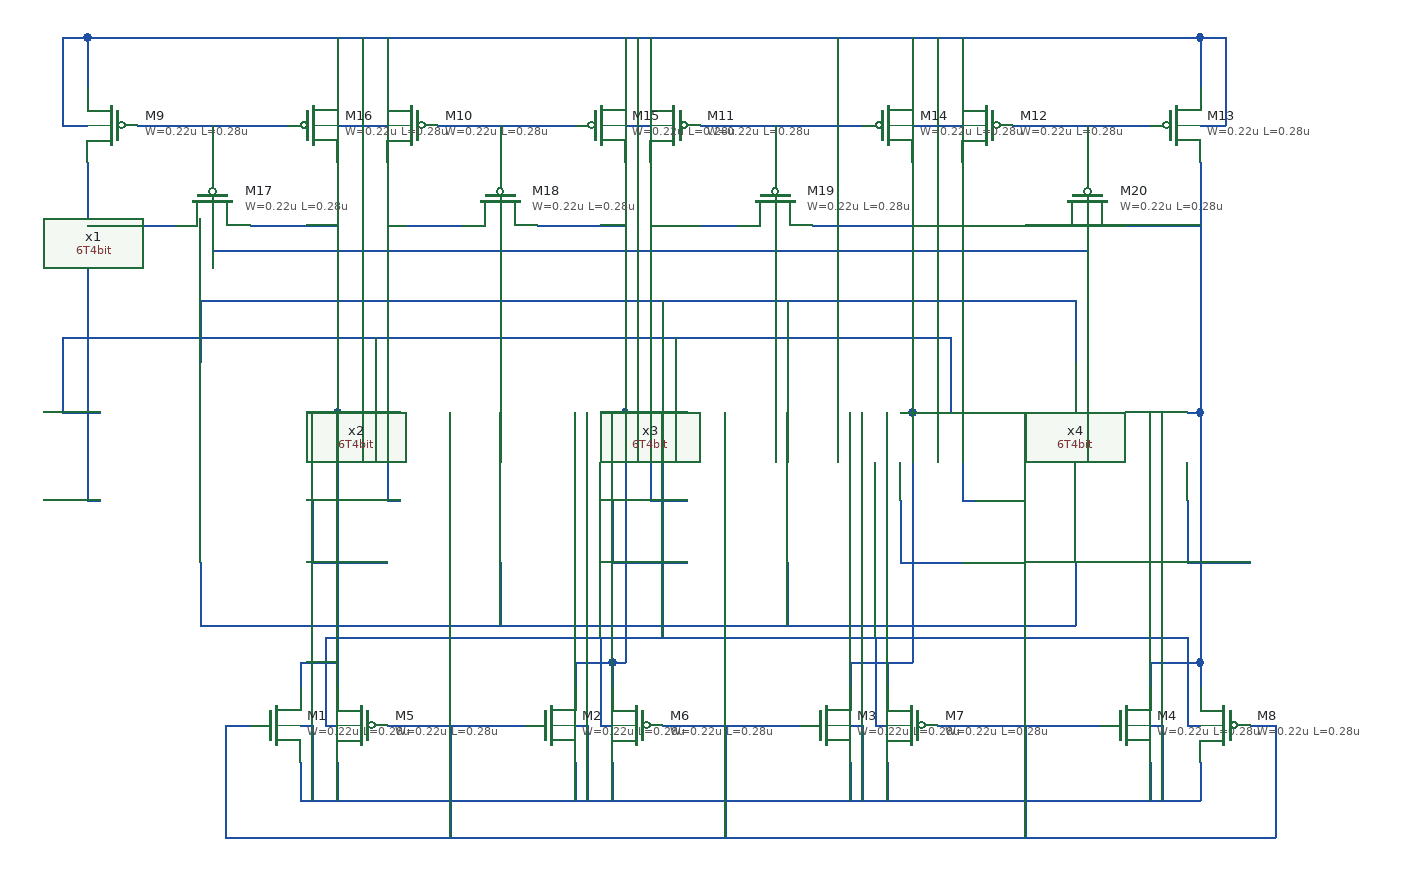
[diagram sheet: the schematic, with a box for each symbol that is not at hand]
v {xschem version=3.4.8RC file_version=1.3}
G {}
K {}
V {}
S {}
F {}
E {}
N 550 -130 550 -80 {lab=#net1}
N -150 -130 550 -130 {lab=#net1}
N -150 -130 -150 -80 {lab=#net1}
N 90 -130 90 -80 {lab=#net1}
N 320 -130 320 -80 {lab=#net1}
N -150 80 -150 130 {lab=#net2}
N -150 130 550 130 {lab=#net2}
N 550 80 550 130 {lab=#net2}
N 320 80 320 130 {lab=#net2}
N 90 80 90 130 {lab=#net2}
N 650 160 650 180 {lab=#net3}
N 610 160 650 160 {lab=#net3}
N 610 160 610 180 {lab=#net3}
N -70 240 -70 270 {lab=#net4}
N -70 270 650 270 {lab=#net4}
N 650 240 650 270 {lab=#net4}
N 610 240 610 270 {lab=#net4}
N 400 240 400 270 {lab=#net4}
N 370 240 370 270 {lab=#net4}
N 180 240 180 270 {lab=#net4}
N 150 240 150 270 {lab=#net4}
N -40 240 -40 270 {lab=#net4}
N -70 160 -70 180 {lab=#net5}
N -70 160 -40 160 {lab=#net5}
N 150 160 150 180 {lab=#net6}
N 150 160 180 160 {lab=#net6}
N 180 160 180 180 {lab=#net6}
N 370 160 370 180 {lab=#net1}
N 400 160 400 180 {lab=#net1}
N 410 -40 420 -40 {lab=#net1}
N 420 -40 420 160 {lab=#net1}
N 390 160 420 160 {lab=#net1}
N 370 160 390 160 {lab=#net1}
N 640 -40 650 -40 {lab=#net3}
N 650 -40 650 160 {lab=#net3}
N 180 -40 190 -40 {lab=#net6}
N 190 -40 190 160 {lab=#net6}
N 180 160 190 160 {lab=#net6}
N -60 -40 -40 -40 {lab=#net5}
N -40 -40 -40 170 {lab=#net5}
N -40 170 -40 180 {lab=#net5}
N -70 210 -60 210 {lab=#net4}
N -60 210 -60 270 {lab=#net4}
N 150 210 160 210 {lab=#net4}
N 160 210 160 270 {lab=#net4}
N 370 210 380 210 {lab=#net4}
N 380 210 380 270 {lab=#net4}
N 610 210 620 210 {lab=#net4}
N 620 210 620 270 {lab=#net4}
N -0 210 110 210 {lab=#net7}
N 220 210 330 210 {lab=#net7}
N 440 210 570 210 {lab=#net7}
N -130 210 -110 210 {lab=#net7}
N -130 210 -130 300 {lab=#net7}
N -130 300 710 300 {lab=#net7}
N 710 210 710 300 {lab=#net7}
N 690 210 710 210 {lab=#net7}
N 510 210 510 300 {lab=#net7}
N 270 210 270 300 {lab=#net7}
N 50 220 50 300 {lab=#net7}
N 50 210 50 220 {lab=#net7}
N -50 210 -40 210 {lab=#net1}
N -50 140 -50 210 {lab=#net1}
N -50 140 640 140 {lab=#net1}
N 640 140 640 210 {lab=#net1}
N 640 210 650 210 {lab=#net1}
N 390 210 400 210 {lab=#net1}
N 390 140 390 210 {lab=#net1}
N 170 210 180 210 {lab=#net1}
N 170 140 170 210 {lab=#net1}
N 220 -130 220 140 {lab=#net1}
N 450 -40 470 -40 {lab=#net8}
N 450 -100 450 -40 {lab=#net8}
N -260 -100 450 -100 {lab=#net8}
N -260 -100 -260 -40 {lab=#net8}
N -260 -40 -230 -40 {lab=#net8}
N -10 -40 10 -40 {lab=#net8}
N -10 -100 -10 -40 {lab=#net8}
N 230 -40 240 -40 {lab=#net8}
N 230 -100 230 -40 {lab=#net8}
N -240 30 -230 30 {lab=#net9}
N -240 -180 -240 30 {lab=#net9}
N -40 -240 -40 -40 {lab=#net5}
N -240 -240 -240 -180 {lab=#net9}
N 0 30 10 30 {lab=#net10}
N -0 -240 -0 30 {lab=#net10}
N 190 -240 190 -40 {lab=#net6}
N 210 30 240 30 {lab=#net11}
N 210 -240 210 30 {lab=#net11}
N 420 -240 420 -40 {lab=#net1}
N 460 30 470 30 {lab=#net12}
N 460 -240 460 30 {lab=#net12}
N 650 -240 650 -40 {lab=#net3}
N -200 -270 -80 -270 {lab=#net13}
N 40 -270 150 -270 {lab=#net14}
N 250 -270 380 -270 {lab=#net15}
N 500 -270 610 -270 {lab=#net16}
N -240 -340 -240 -300 {lab=#net17}
N -240 -340 650 -340 {lab=#net17}
N 650 -340 650 -300 {lab=#net17}
N 460 -340 460 -300 {lab=#net17}
N 420 -340 420 -300 {lab=#net17}
N 210 -340 210 -300 {lab=#net17}
N 190 -340 190 -300 {lab=#net17}
N 0 -340 0 -300 {lab=#net17}
N -40 -340 -40 -300 {lab=#net17}
N -260 -270 -240 -270 {lab=#net17}
N -260 -340 -260 -270 {lab=#net17}
N -260 -340 -240 -340 {lab=#net17}
N -40 -270 -0 -270 {lab=#net17}
N -20 -340 -20 -270 {lab=#net17}
N 190 -270 210 -270 {lab=#net17}
N 200 -340 200 -270 {lab=#net17}
N 420 -270 460 -270 {lab=#net17}
N 440 -340 440 -270 {lab=#net17}
N 650 -270 670 -270 {lab=#net17}
N 670 -340 670 -270 {lab=#net17}
N 650 -340 670 -340 {lab=#net17}
N 590 -190 650 -190 {lab=#net3}
N 460 -190 530 -190 {lab=#net12}
N 560 -270 560 -230 {lab=#net16}
N 340 -190 420 -190 {lab=#net1}
N 210 -190 280 -190 {lab=#net11}
N 310 -270 310 -230 {lab=#net15}
N 120 -190 190 -190 {lab=#net6}
N 0 -190 60 -190 {lab=#net10}
N 90 -270 90 -230 {lab=#net14}
N -110 -190 -40 -190 {lab=#net5}
N -240 -190 -170 -190 {lab=#net9}
N -140 -270 -140 -230 {lab=#net13}
N -140 -190 -140 -170 {lab=#net17}
N -140 -170 560 -170 {lab=#net17}
N 560 -190 560 -170 {lab=#net17}
N 310 -190 310 -170 {lab=#net17}
N 90 -190 90 -170 {lab=#net17}
N 360 -340 360 -170 {lab=#net17}
N -60 30 -60 80 {lab=#net18}
N -60 80 -0 80 {lab=#net18}
N 180 30 180 80 {lab=#net19}
N 180 80 240 80 {lab=#net19}
N 410 30 410 80 {lab=#net20}
N 410 80 460 80 {lab=#net20}
N 640 30 640 80 {lab=#net21}
N 640 80 690 80 {lab=#net21}
C {6T4bit.sym} -210 0 0 0 {name=x1}
C {6T4bit.sym} 30 0 0 0 {name=x2}
C {6T4bit.sym} 260 0 0 0 {name=x3}
C {6T4bit.sym} 490 0 0 0 {name=x4}
C {symbols/nfet_03v3.sym} -90 210 0 0 {name=M1
L=0.28u
W=0.22u
nf=1
m=1
ad="'int((nf+1)/2) * W/nf * 0.18u'"
pd="'2*int((nf+1)/2) * (W/nf + 0.18u)'"
as="'int((nf+2)/2) * W/nf * 0.18u'"
ps="'2*int((nf+2)/2) * (W/nf + 0.18u)'"
nrd="'0.18u / W'" nrs="'0.18u / W'"
sa=0 sb=0 sd=0
model=nfet_03v3
spiceprefix=X
}
C {symbols/nfet_03v3.sym} 130 210 0 0 {name=M2
L=0.28u
W=0.22u
nf=1
m=1
ad="'int((nf+1)/2) * W/nf * 0.18u'"
pd="'2*int((nf+1)/2) * (W/nf + 0.18u)'"
as="'int((nf+2)/2) * W/nf * 0.18u'"
ps="'2*int((nf+2)/2) * (W/nf + 0.18u)'"
nrd="'0.18u / W'" nrs="'0.18u / W'"
sa=0 sb=0 sd=0
model=nfet_03v3
spiceprefix=X
}
C {symbols/nfet_03v3.sym} 350 210 0 0 {name=M3
L=0.28u
W=0.22u
nf=1
m=1
ad="'int((nf+1)/2) * W/nf * 0.18u'"
pd="'2*int((nf+1)/2) * (W/nf + 0.18u)'"
as="'int((nf+2)/2) * W/nf * 0.18u'"
ps="'2*int((nf+2)/2) * (W/nf + 0.18u)'"
nrd="'0.18u / W'" nrs="'0.18u / W'"
sa=0 sb=0 sd=0
model=nfet_03v3
spiceprefix=X
}
C {symbols/nfet_03v3.sym} 590 210 0 0 {name=M4
L=0.28u
W=0.22u
nf=1
m=1
ad="'int((nf+1)/2) * W/nf * 0.18u'"
pd="'2*int((nf+1)/2) * (W/nf + 0.18u)'"
as="'int((nf+2)/2) * W/nf * 0.18u'"
ps="'2*int((nf+2)/2) * (W/nf + 0.18u)'"
nrd="'0.18u / W'" nrs="'0.18u / W'"
sa=0 sb=0 sd=0
model=nfet_03v3
spiceprefix=X
}
C {symbols/pfet_03v3.sym} -20 210 0 1 {name=M5
L=0.28u
W=0.22u
nf=1
m=1
ad="'int((nf+1)/2) * W/nf * 0.18u'"
pd="'2*int((nf+1)/2) * (W/nf + 0.18u)'"
as="'int((nf+2)/2) * W/nf * 0.18u'"
ps="'2*int((nf+2)/2) * (W/nf + 0.18u)'"
nrd="'0.18u / W'" nrs="'0.18u / W'"
sa=0 sb=0 sd=0
model=pfet_03v3
spiceprefix=X
}
C {symbols/pfet_03v3.sym} 200 210 0 1 {name=M6
L=0.28u
W=0.22u
nf=1
m=1
ad="'int((nf+1)/2) * W/nf * 0.18u'"
pd="'2*int((nf+1)/2) * (W/nf + 0.18u)'"
as="'int((nf+2)/2) * W/nf * 0.18u'"
ps="'2*int((nf+2)/2) * (W/nf + 0.18u)'"
nrd="'0.18u / W'" nrs="'0.18u / W'"
sa=0 sb=0 sd=0
model=pfet_03v3
spiceprefix=X
}
C {symbols/pfet_03v3.sym} 420 210 0 1 {name=M7
L=0.28u
W=0.22u
nf=1
m=1
ad="'int((nf+1)/2) * W/nf * 0.18u'"
pd="'2*int((nf+1)/2) * (W/nf + 0.18u)'"
as="'int((nf+2)/2) * W/nf * 0.18u'"
ps="'2*int((nf+2)/2) * (W/nf + 0.18u)'"
nrd="'0.18u / W'" nrs="'0.18u / W'"
sa=0 sb=0 sd=0
model=pfet_03v3
spiceprefix=X
}
C {symbols/pfet_03v3.sym} 670 210 0 1 {name=M8
L=0.28u
W=0.22u
nf=1
m=1
ad="'int((nf+1)/2) * W/nf * 0.18u'"
pd="'2*int((nf+1)/2) * (W/nf + 0.18u)'"
as="'int((nf+2)/2) * W/nf * 0.18u'"
ps="'2*int((nf+2)/2) * (W/nf + 0.18u)'"
nrd="'0.18u / W'" nrs="'0.18u / W'"
sa=0 sb=0 sd=0
model=pfet_03v3
spiceprefix=X
}
C {symbols/pfet_03v3.sym} -220 -270 0 1 {name=M9
L=0.28u
W=0.22u
nf=1
m=1
ad="'int((nf+1)/2) * W/nf * 0.18u'"
pd="'2*int((nf+1)/2) * (W/nf + 0.18u)'"
as="'int((nf+2)/2) * W/nf * 0.18u'"
ps="'2*int((nf+2)/2) * (W/nf + 0.18u)'"
nrd="'0.18u / W'" nrs="'0.18u / W'"
sa=0 sb=0 sd=0
model=pfet_03v3
spiceprefix=X
}
C {symbols/pfet_03v3.sym} 20 -270 0 1 {name=M10
L=0.28u
W=0.22u
nf=1
m=1
ad="'int((nf+1)/2) * W/nf * 0.18u'"
pd="'2*int((nf+1)/2) * (W/nf + 0.18u)'"
as="'int((nf+2)/2) * W/nf * 0.18u'"
ps="'2*int((nf+2)/2) * (W/nf + 0.18u)'"
nrd="'0.18u / W'" nrs="'0.18u / W'"
sa=0 sb=0 sd=0
model=pfet_03v3
spiceprefix=X
}
C {symbols/pfet_03v3.sym} 230 -270 0 1 {name=M11
L=0.28u
W=0.22u
nf=1
m=1
ad="'int((nf+1)/2) * W/nf * 0.18u'"
pd="'2*int((nf+1)/2) * (W/nf + 0.18u)'"
as="'int((nf+2)/2) * W/nf * 0.18u'"
ps="'2*int((nf+2)/2) * (W/nf + 0.18u)'"
nrd="'0.18u / W'" nrs="'0.18u / W'"
sa=0 sb=0 sd=0
model=pfet_03v3
spiceprefix=X
}
C {symbols/pfet_03v3.sym} 480 -270 0 1 {name=M12
L=0.28u
W=0.22u
nf=1
m=1
ad="'int((nf+1)/2) * W/nf * 0.18u'"
pd="'2*int((nf+1)/2) * (W/nf + 0.18u)'"
as="'int((nf+2)/2) * W/nf * 0.18u'"
ps="'2*int((nf+2)/2) * (W/nf + 0.18u)'"
nrd="'0.18u / W'" nrs="'0.18u / W'"
sa=0 sb=0 sd=0
model=pfet_03v3
spiceprefix=X
}
C {symbols/pfet_03v3.sym} 630 -270 0 0 {name=M13
L=0.28u
W=0.22u
nf=1
m=1
ad="'int((nf+1)/2) * W/nf * 0.18u'"
pd="'2*int((nf+1)/2) * (W/nf + 0.18u)'"
as="'int((nf+2)/2) * W/nf * 0.18u'"
ps="'2*int((nf+2)/2) * (W/nf + 0.18u)'"
nrd="'0.18u / W'" nrs="'0.18u / W'"
sa=0 sb=0 sd=0
model=pfet_03v3
spiceprefix=X
}
C {symbols/pfet_03v3.sym} 400 -270 0 0 {name=M14
L=0.28u
W=0.22u
nf=1
m=1
ad="'int((nf+1)/2) * W/nf * 0.18u'"
pd="'2*int((nf+1)/2) * (W/nf + 0.18u)'"
as="'int((nf+2)/2) * W/nf * 0.18u'"
ps="'2*int((nf+2)/2) * (W/nf + 0.18u)'"
nrd="'0.18u / W'" nrs="'0.18u / W'"
sa=0 sb=0 sd=0
model=pfet_03v3
spiceprefix=X
}
C {symbols/pfet_03v3.sym} 170 -270 0 0 {name=M15
L=0.28u
W=0.22u
nf=1
m=1
ad="'int((nf+1)/2) * W/nf * 0.18u'"
pd="'2*int((nf+1)/2) * (W/nf + 0.18u)'"
as="'int((nf+2)/2) * W/nf * 0.18u'"
ps="'2*int((nf+2)/2) * (W/nf + 0.18u)'"
nrd="'0.18u / W'" nrs="'0.18u / W'"
sa=0 sb=0 sd=0
model=pfet_03v3
spiceprefix=X
}
C {symbols/pfet_03v3.sym} -60 -270 0 0 {name=M16
L=0.28u
W=0.22u
nf=1
m=1
ad="'int((nf+1)/2) * W/nf * 0.18u'"
pd="'2*int((nf+1)/2) * (W/nf + 0.18u)'"
as="'int((nf+2)/2) * W/nf * 0.18u'"
ps="'2*int((nf+2)/2) * (W/nf + 0.18u)'"
nrd="'0.18u / W'" nrs="'0.18u / W'"
sa=0 sb=0 sd=0
model=pfet_03v3
spiceprefix=X
}
C {symbols/pfet_03v3.sym} -140 -210 1 0 {name=M17
L=0.28u
W=0.22u
nf=1
m=1
ad="'int((nf+1)/2) * W/nf * 0.18u'"
pd="'2*int((nf+1)/2) * (W/nf + 0.18u)'"
as="'int((nf+2)/2) * W/nf * 0.18u'"
ps="'2*int((nf+2)/2) * (W/nf + 0.18u)'"
nrd="'0.18u / W'" nrs="'0.18u / W'"
sa=0 sb=0 sd=0
model=pfet_03v3
spiceprefix=X
}
C {symbols/pfet_03v3.sym} 90 -210 1 0 {name=M18
L=0.28u
W=0.22u
nf=1
m=1
ad="'int((nf+1)/2) * W/nf * 0.18u'"
pd="'2*int((nf+1)/2) * (W/nf + 0.18u)'"
as="'int((nf+2)/2) * W/nf * 0.18u'"
ps="'2*int((nf+2)/2) * (W/nf + 0.18u)'"
nrd="'0.18u / W'" nrs="'0.18u / W'"
sa=0 sb=0 sd=0
model=pfet_03v3
spiceprefix=X
}
C {symbols/pfet_03v3.sym} 310 -210 1 0 {name=M19
L=0.28u
W=0.22u
nf=1
m=1
ad="'int((nf+1)/2) * W/nf * 0.18u'"
pd="'2*int((nf+1)/2) * (W/nf + 0.18u)'"
as="'int((nf+2)/2) * W/nf * 0.18u'"
ps="'2*int((nf+2)/2) * (W/nf + 0.18u)'"
nrd="'0.18u / W'" nrs="'0.18u / W'"
sa=0 sb=0 sd=0
model=pfet_03v3
spiceprefix=X
}
C {symbols/pfet_03v3.sym} 560 -210 1 0 {name=M20
L=0.28u
W=0.22u
nf=1
m=1
ad="'int((nf+1)/2) * W/nf * 0.18u'"
pd="'2*int((nf+1)/2) * (W/nf + 0.18u)'"
as="'int((nf+2)/2) * W/nf * 0.18u'"
ps="'2*int((nf+2)/2) * (W/nf + 0.18u)'"
nrd="'0.18u / W'" nrs="'0.18u / W'"
sa=0 sb=0 sd=0
model=pfet_03v3
spiceprefix=X
}
